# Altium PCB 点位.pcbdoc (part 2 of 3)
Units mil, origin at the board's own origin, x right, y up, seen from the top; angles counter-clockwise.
Board outline 2817.44 x 1578.14 mil, 2 copper layers (Top Layer, Bottom Layer); 132 components, 113 nets, 538 pads, 285 vias.

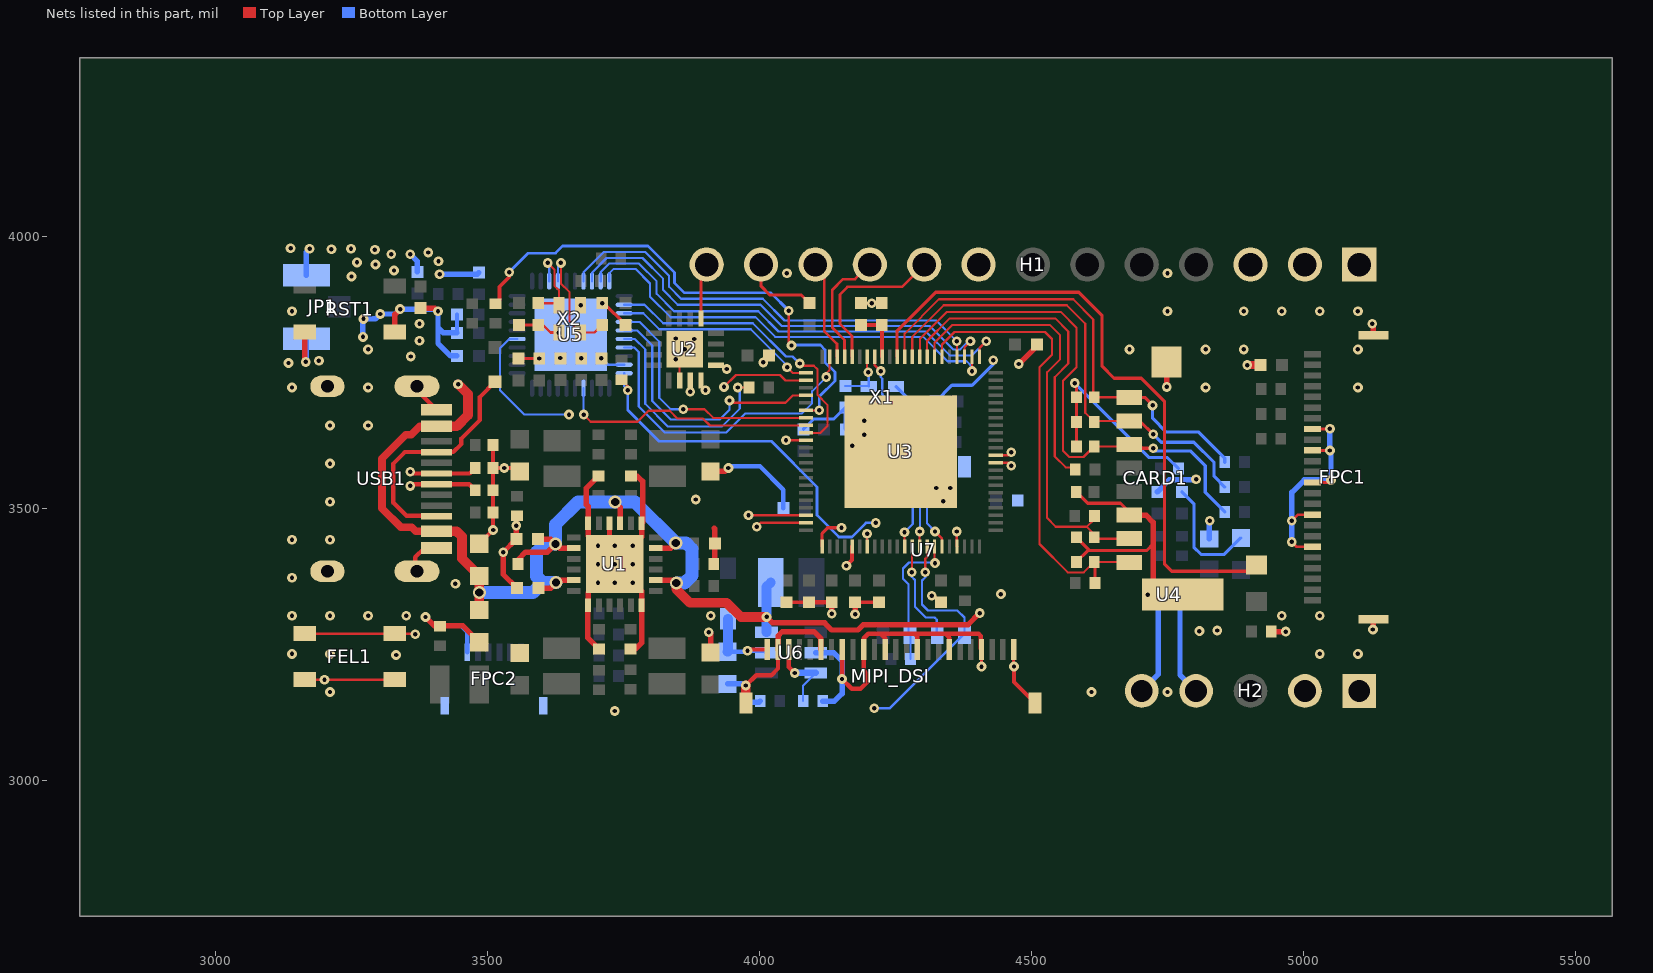
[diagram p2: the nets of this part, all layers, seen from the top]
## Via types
v1: diameter 18, hole 8, Top Layer to Bottom Layer, 271 vias
v2: diameter 24, hole 15, Top Layer to Bottom Layer, 14 vias

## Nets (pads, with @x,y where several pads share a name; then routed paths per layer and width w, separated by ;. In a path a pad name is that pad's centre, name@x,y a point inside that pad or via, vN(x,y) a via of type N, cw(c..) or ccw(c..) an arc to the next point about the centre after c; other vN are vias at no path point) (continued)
GND: C1.1 C2.1 C3.1 C4.1 C5.2 C6.1 C7.1 C8.1 C9.1 C10.2 C11.2 C13.1 C14.1 C15.2 C16.2 C17.1 C18.1 C19.1 C20.1 C21.2 C22.2 C23.2 C24.2 C25.2 C26.2 C27.2 C28.2 C29.2 C30.2 C31.2 C32.1 C33.2 C34.2 C35.1 C36.1 C37.1 C38.1 C39.2 C40.1 C41.1 C42.1 C43.1 C44.1 C45.1 C46.1 C47.1 CARD1.6 CARD1.9 CARD1.10 D1.2 D2.2 D3.2 D4.2 D6.1 D8.2 D9.2 D10.2 D11.2 D12.2 D13.2 FEL1.3 FEL1.4 FPC1.8 FPC1.10 FPC1.13 FPC1.16 FPC1.19 FPC1.25 FPC1.26 FPC2.6 FPC2.7 FPC2.8 H1.1 H1.12 H2.1 JP1.2 JP1.3 MIPI_DSI.1 MIPI_DSI.4 MIPI_DSI.7 MIPI_DSI.10 MIPI_DSI.13 MIPI_DSI.15 MIPI_DSI.17 MIPI_DSI.19 MIPI_DSI.23 MIPI_DSI.25 MIPI_DSI.26 R2.2 R5.2 R9.1 R11.2 R13.2 R23.1 R24.1 R25.2 R26.2 R27.1 RST1.1 RST1.2 U1.1 U1.4 U1.6 U1.13 U1.18 U1.25 U2.2 U2.17 U3.51 U3.89 U4.A2 U4.B3 U5.19 U5.41 U6.2 U7.4 USB1.12 USB1.13 USB1.14 USB1.15 USB1.A1B12 USB1.B1A12 X1.2 X1.4 X2.2 X2.4 | length 7017.8
  Top Layer w4: v1(3845.5,3812.13) 3852.72,3804.92 U2.2@3852.72,3735.05 ; U3.51@4197.49,3429.62 v1(4197.49,3453.12) ; v1(4316.5,3339.13) 4321.51,3339.13 C45.1@4333.5,3327.14
  Top Layer w5: FEL1.3@3165.8,3184.83 v1(3199.94,3184.83) FEL1.4@3331.2,3184.83 ; C21.2@3556.67,3775.24 v1(3594.67,3775.24) ; C23.2@3557.85,3836.98 3592.84,3836.98 3601.64,3836.99 3615.65,3822.99 v1(3630.85,3822.99) ; C17.1@4186.3,3877.05 v1(4206.02,3877.05) 4224.15,3877.05 C18.1@4224.43,3877.33 ; MIPI_DSI.4@4407.8,3240.33 v1(4407.8,3208.83) v1@4408.5,3208.13 ; MIPI_DSI.1@4466.9,3240.33 4466.9,3209.73 v1(4467.5,3209.13) ; v1(4978.5,3438.13) 4987.4,3429.23 FPC1.19@5016.69,3429.18 ; v1(4978.5,3477.13) 4989.6,3488.23 FPC1.16@5016.69,3488.24 ; FPC1.13@5016.69,3547.29 5045.7,3547.33 v1(5050.5,3552.13) ; FPC1.10@5016.7,3606.33 5048.3,3606.33 v1(5048.5,3606.13) ; FPC1.8@5017.1,3646.13 FPC1.8@5016.69,3645.72 5048.1,3645.73 v1(5048.5,3646.13)
  Top Layer w6: v1(3552.5,3468.13) 3553.5,3469.13 R27.1@3553.5,3486.13 ; v1(3710.5,3877.14) 3713.5,3877.14 C41.1@3753.5,3837.14 ; H1.12@4002.5,3948.13 4002.5,3908.13 4018.5,3892.13 4076.49,3892.13 C40.1@4091.5,3877.13 ; C38.1@4049.5,3327.14 C37.1@4090.5,3327.14 ; C11.2@4175.5,3327.13 C44.1@4219.5,3327.14 ; v1(4579.5,3730.13) 4582.44,3727.19 D13.2@4582.44,3704.21 D12.2@4582.44,3658.84 D11.2@4582.44,3613.47 ; D10.2@4582.1,3530.13 4603.1,3509.13 4663.42,3509.13 CARD1.6@4685.32,3487.23 ; D8.2@4582.44,3401.36 4603.22,3422.13 4607.04,3422.13 ; D9.2@4582.44,3446.73 4607.04,3422.13 ; 4723.5,3434.41 4711.22,3422.13 4607.04,3422.13
  Top Layer w7: C3.1@3484.5,3434.66 v1(3509.9,3460.06) D2.2@3509.9,3492.13 D3.2@3509.9,3533.13 D4.2@3509.9,3574.13 ; D1.2@3509.9,3616.13 D4.2@3509.9,3574.13 ; C4.1@3558.67,3567.75 3552.29,3574.13 v1(3530.37,3574.13) D4.2@3509.9,3574.13 ; v1(4467.5,3209.13) 4467.5,3180.73 MIPI_DSI.26@4506.3,3141.93
  Top Layer w8: USB1.13@3369.8,3384.03 3366.5,3387.33 3366.5,3410.13 3383.5,3427.13 USB1.B1A12@3405.8,3427.13 ; USB1.12@3369.8,3724.23 3369.8,3717.13 USB1.A1B12@3405.8,3681.13 ; v1(3974.5,3174.13) 3993.5,3193.13 4021.5,3193.13 4033.8,3205.43 MIPI_DSI.23@4033.8,3240.33 ; MIPI_DSI.17@4151.9,3240.33 4151.9,3186.53 v1(4151.5,3186.13) 4169.5,3168.13 4185.5,3168.13 4197.5,3180.13 4197.5,3195.13 4191.3,3201.33 MIPI_DSI.15@4191.3,3240.33 4191.3,3260.93 4199.5,3269.13 4222.5,3269.13 ; MIPI_DSI.13@4230.7,3240.33 4230.7,3260.93 4222.5,3269.13 ; MIPI_DSI.10@4289.7,3240.33 4289.5,3240.53 4289.5,3264.13 4284.5,3269.13 ; MIPI_DSI.7@4348.8,3240.33 4348.5,3240.63 4348.5,3262.13 4341.5,3269.13 ; MIPI_DSI.4@4407.8,3240.33 4406.5,3241.63 4406.5,3265.13 4402.5,3269.13 4341.5,3269.13 ; 4222.5,3269.13 4284.5,3269.13 ; 4284.5,3269.13 4341.5,3269.13
  Top Layer w9: C37.1@4090.5,3327.14 C10.2@4132.5,3327.13
  Top Layer w10: RST1.2@3163.8,3823.83 3163.8,3770.83 v1(3165.5,3769.13) ; RST1.1@3329.2,3823.83 3329.2,3856.45 v1(3338.88,3866.13) ; C5.2@3376.5,3868.13 3402.5,3868.13 v1(3408.5,3862.13) ; v1(3385.5,3300.13) 3401.5,3284.13 3453.97,3284.13 C2.1@3484.5,3253.61 ; v1(3552.5,3468.13) 3552.67,3467.97 C33.2@3552.67,3443.26 v1(3528.5,3419.09) 3528.5,3378.42 C34.2@3553.67,3353.26 ; v1(3702.67,3363.26) 3684.46,3345.05 U1.13@3684.46,3321.99 3683.67,3321.2 3683.67,3262.26 R2.2@3704.67,3241.25 ; v1(3702.67,3431.26) 3684.46,3449.47 U1.6@3684.46,3472.51 3684.46,3503.47 3681.32,3506.61 3681.32,3536.91 R5.2@3703.67,3559.26 ; U1.4@3723.83,3472.51 3723.83,3441.09 v1(3733.67,3431.26) ; R13.2@3762.67,3241.25 3771.67,3241.25 3782.88,3252.47 U1.18@3782.88,3321.99 3782.88,3347.05 v1(3766.67,3363.26) ; R11.2@3763.67,3559.26 3774.67,3559.26 3784.67,3549.26 3784.67,3474.3 U1.1@3782.88,3472.51 3782.88,3447.47 v1(3766.67,3431.26) ; v1(3906.5,3272.13) 3909.67,3268.96 C8.1@3909.67,3234.78 ; R9.1@3915.67,3397.25 3917.67,3399.25 C7.1@3917.67,3435.26 3917.67,3461.97 3916.5,3463.13 ; C6.1@3916.05,3574.13 C6.1@3909.67,3567.75 3936.12,3567.75 v1(3942.5,3574.13) ; MIPI_DSI.23@4033.8,3240.33 4033.8,3265.43 4041.5,3273.13 4099.5,3273.13 4112.5,3260.13 4112.5,3240.43 MIPI_DSI.19@4112.6,3240.33 ; v1(4132.5,3306.13) C10.2@4132.5,3327.13 ; v1(4175.5,3305.13) C11.2@4175.5,3327.13 ; v1(4476.5,3765.13) 4509.51,3798.14 C39.2@4509.51,3801.13 ; CARD1.6@4679.3,3487.23 4685.32,3487.23 4710.4,3487.23 4723.5,3474.13 4723.5,3434.41 4723.5,3350.52 v1(4713.85,3340.88) ; CARD1.10@4748.2,3768.73 4748.2,3723.43 v1(4748.5,3723.13) ; R25.2@4940.5,3273.14 v1(4967.5,3273.14) ; v1(5126.5,3839.13) 5128.3,3837.33 FPC1.26@5128.3,3818.33 ; v1(5127.5,3277.13) 5128.3,3277.93 FPC1.25@5128.31,3295.91
  Top Layer w15: v1(4896.5,3763.13) C35.1@4920.51,3763.13
  Top Layer w18: v1(3974.5,3174.13) 3974.5,3142.23 MIPI_DSI.25@3974.8,3141.93
  Mid-Layer 2 w10: v1(3879.5,3811.13) 3897.5,3811.13 3925.5,3839.13 3977.5,3839.13 4006.5,3810.13 v1(4006.5,3768.13)
  Bottom Layer w4: v1(4192.5,3635.13) v1(4192.5,3661.13) 4200.5,3669.13 X1.4@4200.5,3684.05 ; C15.2@4203.57,3635.13 C15.2@4214.49,3646.05
  Bottom Layer w5: v1(3708.95,3775.71) 3720.65,3764.01 U5.19@3750.9,3764.01 ; v1(4192.5,3635.13) 4203.57,3635.13 4220.5,3635.13 4235.5,3620.13 4263.5,3620.13 4281.5,3638.13 4281.5,3693.05 4278.42,3696.13
  Bottom Layer w6: C43.1@4080.5,3645.13 4099.51,3664.13 4136.58,3664.13 C16.2@4157.5,3685.05 4157.5,3646.13 C42.1@4158.49,3645.13 ; X1.2@4250.5,3724.05 4278.42,3696.13 C36.1@4323.51,3696.13 4353.51,3726.13 4390.5,3726.13 4429.5,3765.13 v1(4429.5,3772.13) ; v1(4579.5,3730.13) 4716.5,3593.13 4749.9,3593.13 D6.1@4769.9,3573.13 ; U4.A2@4732.85,3340.88 U4.B3@4752.85,3320.88 ; C13.1@4776.36,3530.3 4798.5,3508.16 4798.5,3428.13 4811.5,3415.13 4854.58,3415.13 C14.1@4884.85,3445.4
  Bottom Layer w8: v1(3385.5,3300.13) 3400.5,3285.13 3449.5,3285.13 3462.3,3272.33 FPC2.6@3462.3,3235.33 ; C22.2@3443.46,3822.36 C24.2@3443.46,3856.36 ; v1(3942.5,3574.13) 3942.5,3576.13 3943.5,3577.13 4000.5,3577.13 4043.51,3534.13 C46.1@4043.51,3500.13 ; v1(4713.85,3340.88) U4.A2@4732.85,3340.88
  Bottom Layer w10: v1(3165.5,3769.13) 3166.49,3770.12 JP1.3@3166.49,3812.06 ; JP1.2@3166.49,3928.2 3166.49,3971.12 v1(3172.5,3977.13) ; v1(3270.5,3815.13) 3270.5,3847.13 v1(3271.5,3848.13) 3293.5,3848.13 v1(3302.5,3857.13) 3329.88,3857.13 v1(3338.88,3866.13) 3404.5,3866.13 v1(3408.5,3862.13) 3408.5,3832.13 3409.5,3831.13 ; v1(3357.5,3967.13) 3370.64,3953.99 C20.1@3370.64,3934.48 ; v1(3411.5,3930.13) 3480.29,3930.13 C19.1@3483.64,3933.48 ; C22.2@3443.46,3822.36 3418.27,3822.36 3409.5,3831.13 ; C27.2@3443.49,3780.13 3431.5,3780.13 3408.5,3803.13 3408.5,3830.13 3409.5,3831.13 ; C32.1@3940.92,3177.01 3971.62,3177.01 v1(3974.5,3174.13) 3974.5,3153.13 3984.5,3143.13 3998.52,3143.13 R23.1@4000.92,3145.53 ; U6.2@4103.12,3234.54 4136.1,3234.54 4151.5,3219.13 v1(4151.5,3186.13) 4151.5,3159.13 4137.5,3145.13 4116.32,3145.13 R24.1@4115.92,3145.54 ; v1(4978.5,3438.13) v1(4978.5,3477.13) 4978.5,3529.13 5001.5,3552.13 v1(5050.5,3552.13) 5050.5,3604.13 v1(5048.5,3606.13) v1(5048.5,3646.13)
  other v1: 3733.5,3127.13 3210,3162.14 4610,3162.14 4750,3162.14 3331.5,3230.13 3140,3232.14 3210,3232.14 5030,3232.14 5100,3232.14 3140,3302.14 3210,3302.14 3280,3302.14 3350,3302.14 3910,3302.14 4960,3302.14 5030,3302.14 4443.5,3342.13 3440.5,3361.13 3733.67,3363.26 3140,3372.14 3702.67,3397.26 3733.67,3397.26 3766.67,3397.26 3140,3442.14 3210,3442.14 3210,3512.14 4337.5,3513.13 3882.5,3516.13 4324.5,3537.13 4350.5,3537.13 3210,3582.14 4170.5,3615.13 3210,3652.14 3280,3652.14 3140,3722.14 3280,3722.14 4820,3722.14 5100,3722.14 3133.5,3767.13 3189.5,3771.13 3845.5,3774.13 3633.5,3776.13 3671.95,3775.71 3358.5,3779.13 3280,3792.14 3862.51,3792.13 4680,3792.14 4820,3792.14 4890,3792.14 5100,3792.14 3374.5,3807.83 3374.5,3839.13 3140,3862.14 4750,3862.14 4890,3862.14 4960,3862.14 5030,3862.14 5100,3862.14 3670.85,3872.99 3249.5,3926.13 4050,3932.14 4750,3932.14 3327.5,3937.13 3293.5,3948.13 3259.5,3952.13 3409.5,3954.13 3322.5,3967.13 3390.5,3970.13 3292.5,3975.13 3212.5,3976.13 3248.5,3977.13 3137.5,3978.13
HX1: C30.1 U5.3 X2.1 | length 160.9
  Top Layer w4: C30.1@3592.85,3876.99 3626.85,3876.99 X2.1@3630.85,3872.99 3630.85,3900.78 3622.5,3909.13 3622.5,3939.13 v1(3610.5,3951.13)
  Bottom Layer w4: v1(3610.5,3951.13) 3613.13,3948.5 U5.3@3613.13,3917.53
HX2: C31.1 U5.4 X2.3 | length 224.6
  Top Layer w4: v1(3634.5,3951.13) 3634.5,3913.13 3650.5,3897.13 3650.5,3843.34 X2.3@3670.85,3822.99 3696.35,3822.99 C31.1@3710.5,3837.14
  Bottom Layer w4: U5.4@3628.88,3917.53 3628.88,3945.51 v1(3634.5,3951.13)
HXIN: C16.1 U3.16 X1.1 | length 99.2
  Top Layer w4: U3.16@4197.49,3778.64 4197.49,3752.14 v1(4199.5,3750.13)
  Bottom Layer w4: C16.1@4157.5,3725.05 4199.5,3725.05 X1.1@4200.5,3724.05 4200.5,3749.14 v1(4199.5,3750.13)
HXOUT: C15.1 U3.15 X1.3 | length 150.5
  Top Layer w4: U3.15@4211.27,3778.64 4211.27,3763.36 v1(4222.5,3752.13)
  Bottom Layer w4: v1(4222.5,3752.13) 4222.5,3741.13 4225.5,3738.13 4225.5,3709.05 X1.3@4250.5,3684.05 4254.49,3680.06 C15.1@4254.49,3646.05
LED: LED1.2 U3.12 | length 1184.7
  Top Layer w6: U3.12@4252.61,3778.64 4252.61,3826.24 4323.5,3897.13 4586.5,3897.13 4629.5,3854.13 4629.5,3761.13 4651.5,3739.13 4701.5,3739.13 4744.5,3696.13 4744.5,3397.13 4757.5,3384.13 4902.04,3384.13 LED1.2@4913.5,3395.6
LEDA: C32.2 D7.1 MIPI_DSI.24 U6.5 | length 172.8
  Top Layer w8: v1(3977.5,3238.13) 3979.7,3240.33 MIPI_DSI.24@4014.1,3240.33
  Bottom Layer w8: C32.2@3940.92,3236.06 3975.43,3236.06 v1(3977.5,3238.13) 4009.12,3238.13 U6.5@4012.72,3234.54
  Bottom Layer w18: C32.2@3940.92,3236.06 3941.5,3236.64 D7.1@3941.5,3296.93
LEDK: MIPI_DSI.22 R24.2 U6.3 | length 147.6
  Top Layer w8: MIPI_DSI.22@4053.5,3240.33 4053.5,3208.13 v1(4064.5,3197.13)
  Bottom Layer w4: R24.2@4079.92,3145.54 4079.92,3173.94 U6.3@4103.12,3197.14
  Bottom Layer w12: v1(4064.5,3197.13) U6.3@4103.12,3197.14
LINEOUTP: C12.1 U3.49 | length 1142.3
  Top Layer w7: v1(4159.5,3394.13) 4169.93,3404.56 U3.49@4169.93,3429.62
  Mid-Layer 1 w7: v1(4159.5,3394.13) 4302.5,3251.13 4456.5,3251.13 4491.5,3286.13 4796.5,3286.13 v1(4808.5,3274.13)
  Mid-Layer 2 w7: v1(4802.5,3553.13) 4807.5,3548.13 4807.5,3467.13 4823.5,3451.13 4823.5,3289.13 v1(4808.5,3274.13)
  Bottom Layer w10: C12.1@4731.05,3530.3 4752.88,3552.13 4798.5,3552.13 4799.5,3553.13 v1(4802.5,3553.13)
LPCLK: R18.1 U3.63 U5.20 | length 871.8
  Top Layer w4: R18.1@3745.67,3736.24 3757.5,3724.41 v1(3757.5,3717.13)
  Top Layer w5: v1(4362.5,3457.13) 4362.5,3429.97 U3.63@4362.85,3429.62
  Mid-Layer 1 w5: v1(4213.5,3473.13) 4346.5,3473.13 v1(4362.5,3457.13)
  Bottom Layer w4: U5.20@3750.9,3748.26 3750.9,3723.73 v1(3757.5,3717.13)
  Bottom Layer w5: v1(3757.5,3717.13) 3757.5,3680.13 3814.5,3623.13 4021.5,3623.13 4105.5,3539.13 4105.5,3487.21 4145.58,3447.13 4169.5,3447.13 4195.5,3473.13 v1(4213.5,3473.13)
PE10: H1.8 U3.32 | length 573
  Top Layer w5: v1(4048.5,3625.13) 4048.83,3624.8 U3.32@4084.99,3624.8
  Mid-Layer 2 w4: v1(4048.5,3625.13) 4087.5,3664.13 4087.5,3747.13 4144.5,3804.13 4187.5,3804.13 4289.5,3906.13 4360.5,3906.13 H1.8@4402.5,3948.13
PE11: H1.11 U3.20 | length 186
  Top Layer w5: H1.11@4102.5,3948.13 4118.5,3932.13 4118.5,3826.13 4142.37,3802.26 U3.20@4142.37,3778.64
PE12: H1.10 U3.19 | length 220.3
  Top Layer w5: U3.19@4156.15,3778.64 4156.15,3809.48 4133.5,3832.13 4133.5,3901.13 4153.5,3921.13 4175.5,3921.13 H1.10@4202.5,3948.13
PE13: H1.9 U3.18 | length 301.6
  Top Layer w5: U3.18@4169.93,3778.64 4169.93,3816.7 4147.5,3839.13 4147.5,3893.13 4161.5,3907.13 4261.5,3907.13 H1.9@4302.5,3948.13
PH0: H2.2 U3.45 | length 1113.8
  Top Layer w6: U3.45@4114.81,3429.62 4114.81,3453.68 4125.26,3464.13 v1(4150.5,3464.13)
  Mid-Layer 1 w6: v1(4150.5,3464.13) 4132.5,3446.13 4132.5,3398.13 4295.5,3235.13 4947.5,3235.13 5002.5,3180.13 H2.2@5002.5,3164.13
SDC0_CLK: R42.1 U3.8 | length 604
  Top Layer w4: U3.8@4307.73,3778.64 4307.73,3807.36 4349.5,3849.13 4543.5,3849.13 4567.5,3825.13 4567.5,3766.13 4542.5,3741.13 4542.5,3595.13 4562.5,3575.13 4576.51,3575.13 R42.1@4580.5,3571.14
SDC0_CMD: CARD1.3 D11.1 R31.1 U3.9 | length 982.1
  Top Layer w4: U3.9@4293.95,3778.64 4294.5,3779.19 4294.5,3811.13 4344.5,3861.13 4553.5,3861.13 4582.5,3832.13 4582.5,3759.13 4557.5,3734.13 4557.5,3606.13 4569.5,3594.13 4595.5,3594.13 4614.83,3613.47 D11.1@4615.24,3613.47 4675.63,3613.47 CARD1.3@4679.3,3617.13
  Top Layer w6: CARD1.3@4679.3,3617.13 4696.5,3617.13 4703.5,3610.13 v1(4723.5,3610.13)
  Bottom Layer w6: v1(4723.5,3610.13) 4728.5,3605.13 4792.5,3605.13 4819.5,3578.13 4819.5,3529.15 R31.1@4855.34,3493.31
SDC0_D0: CARD1.7 D9.1 R29.1 U3.7 | length 819.7
  Top Layer w4: U3.7@4321.51,3778.64 4321.51,3804.14 4354.5,3837.13 4533.5,3837.13 4552.5,3818.13 4552.5,3774.13 4528.5,3750.13 4528.5,3482.13 4544.5,3466.13 4601.5,3466.13 ; R29.1@4615.5,3486.13 4615.5,3480.13 4601.5,3466.13 ; CARD1.7@4679.3,3443.93 4618.04,3443.93 D9.1@4615.24,3446.73 4615.24,3452.39 4601.5,3466.13
SDC0_D1: CARD1.8 D8.1 R28.1 U3.6 | length 863.2
  Top Layer w4: U3.6@4335.29,3778.64 4335.29,3801.14 4358.29,3824.13 4524.5,3824.13 4537.5,3811.13 4537.5,3782.13 4514.5,3759.13 4514.5,3434.13 4566.5,3382.13 4596.02,3382.13 4613.78,3399.9 D8.1@4615.24,3401.36 ; D8.1@4611.72,3401.36 D8.1@4615.24,3401.36 ; CARD1.8@4679.3,3400.63 4678.58,3401.36 D8.1@4615.24,3401.36
  Top Layer w6: D8.1@4613.78,3399.9 4616.5,3397.18 R28.1@4616.5,3362.13
SDC0_D2: CARD1.1 D13.1 R33.1 U3.11 | length 882.7
  Top Layer w4: U3.11@4266.39,3778.64 4266.5,3778.75 4266.5,3821.13 4329.5,3884.13 4576.5,3884.13 4613.5,3847.13 4613.5,3705.95 D13.1@4615.24,3704.21 4678.83,3704.21 CARD1.1@4679.3,3703.73
  Top Layer w6: CARD1.1@4679.3,3703.73 4707.9,3703.73 v1(4722.5,3689.13)
  Bottom Layer w6: v1(4722.5,3689.13) 4722.5,3665.13 4747.5,3640.13 4807.5,3640.13 4855.34,3592.29 R33.1@4855.34,3584.68
SDC0_D3: CARD1.2 D12.1 R32.1 U3.10 | length 885.8
  Top Layer w4: U3.10@4280.17,3778.64 4280.5,3778.97 4280.5,3815.13 4338.5,3873.13 4564.5,3873.13 4598.5,3839.13 4598.5,3675.58 D12.1@4615.24,3658.84 4616.84,3660.43 CARD1.2@4679.3,3660.43
  Top Layer w6: CARD1.2@4679.3,3660.43 4699.2,3660.43 v1(4723.5,3636.13)
  Bottom Layer w6: v1(4723.5,3636.13) 4738.5,3621.13 4798.5,3621.13 4835.5,3584.13 4835.5,3558.83 R32.1@4855.34,3538.99
SDC1_CLK: R22.1 U5.16 | length 413.2
  Top Layer w4: v1(3959.5,3722.13) R22.1@3980.5,3722.14
  Bottom Layer w4: U5.16@3750.9,3811.26 3770.37,3811.26 3789.5,3792.13 3789.5,3692.13 3831.5,3650.13 3930.5,3650.13 3963.5,3683.13 3963.5,3718.13 v1(3959.5,3722.13)
SDC1_CMD: U3.31 U5.12 | length 561.1
  Top Layer w4: v1(4073.5,3766.13) 4077.5,3762.13 4099.5,3762.13 4106.5,3755.13 4106.5,3708.13 4124.5,3690.13 4124.5,3651.13 4111.95,3638.58 U3.31@4084.99,3638.58
  Bottom Layer w4: U5.12@3750.9,3874.25 3788.38,3874.25 3822.5,3840.13 3987.5,3840.13 4048.5,3779.13 4060.5,3779.13 v1(4073.5,3766.13)
SDC1_D0: U3.23 U5.13 | length 381.3
  Top Layer w4: v1(4050.5,3759.13) 4060.81,3748.82 U3.23@4084.99,3748.82
  Bottom Layer w4: U5.13@3750.9,3858.5 3786.13,3858.5 3815.5,3829.13 3983.5,3829.13 4050.5,3762.13 v1(4050.5,3759.13)
SDC1_D1: U3.29 U5.14 | length 467.6
  Top Layer w4: v1(3859.5,3682.13) 3898.5,3682.13 3914.49,3666.14 U3.29@4084.99,3666.14
  Bottom Layer w4: U5.14@3750.9,3842.75 3778.88,3842.75 3815.5,3806.13 3815.5,3703.13 3836.5,3682.13 v1(3859.5,3682.13)
SDC1_D2: U3.21 U5.17 | length 590.1
  Top Layer w4: v1(4122.5,3741.13) 4122.5,3748.13 4128.59,3754.22 U3.21@4128.59,3778.64
  Bottom Layer w4: U5.17@3750.9,3795.51 3769.12,3795.51 3777.5,3787.13 3777.5,3687.13 3825.5,3639.13 3938.5,3639.13 3973.5,3674.13 4077.5,3674.13 4096.5,3693.13 4096.5,3715.13 v1(4122.5,3741.13)
SDC1_D3: U3.26 U5.15 | length 493.4
  Top Layer w4: v1(3944.5,3698.13) 3948.5,3694.13 4047.5,3694.13 4060.85,3707.48 U3.26@4084.99,3707.48
  Bottom Layer w4: U5.15@3750.9,3827 3774.63,3827 3802.5,3799.13 3802.5,3697.13 3836.5,3663.13 3926.5,3663.13 3944.5,3681.13 v1(3944.5,3698.13)
SPI0_CLK: U3.57 U7.6 | length 189.1
  Top Layer w4: v1(4279.5,3382.13) 4280.17,3382.8 U3.57@4280.17,3429.62
  Bottom Layer w4: v1(4279.5,3382.13) 4279.5,3374.13 4285.5,3368.13 4285.5,3319.13 4305.5,3299.13 4321.5,3299.13 4325.5,3295.13 4325.5,3270.63 U7.6@4326.5,3269.63
SPI0_CS: R34.1 U3.56 U7.1 | length 339.8
  Top Layer w4: U3.56@4266.39,3429.62 4266.5,3456.13 v1(4266.39,3456.02)
  Bottom Layer w4: U7.1@4226.5,3576.63 4226.5,3556.13 4236.5,3546.13 4256.5,3546.13 4262.5,3540.13 4262.5,3526.13 4281.5,3507.13 4281.5,3471.13 v1(4266.39,3456.02)
  Bottom Layer w5: U7.1@4226.5,3576.63 4226.5,3589.13 4244.5,3607.13 4294.5,3607.13 4307.5,3620.13 4307.5,3640.12 R34.1@4325.5,3658.13
SPI0_HOLD: R36.1 U3.60 U7.7 | length 266.7
  Top Layer w4: U3.60@4321.51,3429.62 4321.51,3400.12 v1(4322.5,3399.13)
  Bottom Layer w4: R36.1@4277.5,3223.14 4277.5,3268.63 U7.7@4276.5,3269.63 4273.5,3272.63 4273.5,3360.13 4263.5,3370.13 4263.5,3389.13 4274.5,3400.13 4321.5,3400.13 v1(4322.5,3399.13)
SPI0_MISO: U3.58 U7.2 | length 154.7
  Top Layer w4: U3.58@4293.95,3429.62 4293.95,3456.58 v1(4294.5,3457.13)
  Bottom Layer w4: U7.2@4276.5,3576.63 4276.5,3531.13 4294.5,3513.13 v1(4294.5,3457.13)
SPI0_MOSI: FEL1.1 FEL1.2 U3.59 U7.5 | length 1587.1
  Top Layer w4: v1(4304.5,3382.13) 4304.5,3407.13 4307.73,3410.36 U3.59@4307.73,3429.62
  Top Layer w5: FEL1.1@3165.8,3269.43 3331.2,3269.43 3365.2,3269.43 v1(3366.5,3268.13)
  Mid-Layer 1 w6: v1(3366.5,3268.13) 3382.5,3284.13 3410.5,3284.13 3436.5,3310.13 3623.5,3310.13 3756.5,3177.13 3799.5,3177.13 3844.5,3132.13 v1(4210.5,3132.13)
  Bottom Layer w4: v1(4304.5,3382.13) 4304.5,3373.13 4298.5,3367.13 4298.5,3323.13 4309.5,3312.13 4363.5,3312.13 4376.5,3299.13 U7.5@4376.5,3269.63
  Bottom Layer w5: v1(4210.5,3132.13) 4239,3132.13 U7.5@4376.5,3269.63
SPI0_WP: R35.1 U3.61 U7.3 | length 224.8
  Top Layer w4: v1(4322.5,3457.13) 4335.28,3444.35 U3.61@4335.28,3429.62
  Bottom Layer w4: v1(4322.5,3457.13) 4307.5,3472.13 4307.5,3519.13 4293.5,3533.13 4293.5,3545.13 4325,3576.63 U7.3@4326.5,3576.63 4325.5,3577.63 R35.1@4325.5,3622.13
SPK+: H2.4 U4.C3 | length 169
  Bottom Layer w10: U4.C3@4772.85,3320.88 4772.85,3193.78 H2.4@4802.5,3164.13
SPK-: H2.5 U4.A3 | length 169.3
  Bottom Layer w10: H2.5@4702.5,3164.13 4732.85,3194.49 U4.A3@4732.85,3320.88
UART0_RX: H1.3 U2.4 U3.42 | length 1842.1
  Top Layer w4: U2.4@3892.09,3735.04 3892.09,3725.55 v1(3900.5,3717.13) ; v1(3979.5,3487.13) 3979.63,3487 U3.42@4084.99,3487
  Mid-Layer 1 w5: v1(3900.5,3717.13) 3923.5,3740.13 3954.5,3740.13 3955.5,3741.13 4023.5,3741.13 4081.28,3683.35 4081.28,3512.91 4055.5,3487.13 v1(3979.5,3487.13)
  Mid-Layer 2 w4: v1(3979.5,3487.13) 3987.5,3495.13 4161.5,3495.13 4294.5,3628.13 4294.5,3805.13 4329.5,3840.13 4794.5,3840.13 H1.3@4902.5,3948.13
UART0_TX: H1.2 U2.5 U3.43 | length 1905.5
  Top Layer w4: U2.5@3919.59,3762.61 3933.02,3762.61 v1(3939.5,3756.13) ; v1(3994.5,3466.13) 4001.59,3473.22 U3.43@4084.99,3473.22
  Mid-Layer 1 w5: v1(3939.5,3756.13) 3943.5,3752.13 4029.5,3752.13 4092.28,3689.35 4092.28,3506.91 4059.5,3474.13 4002.5,3474.13 v1(3994.5,3466.13)
  Mid-Layer 2 w4: v1(3994.5,3466.13) 4009.5,3481.13 4168.5,3481.13 4307.5,3620.13 4307.5,3798.13 4334.5,3825.13 4879.5,3825.13 H1.2@5002.5,3948.13
UART2_CTS: U3.4 U5.7 | length 826.4
  Top Layer w4: v1(4362.5,3807.13) 4362.85,3806.78 U3.4@4362.85,3778.64
  Bottom Layer w4: U5.7@3676.12,3917.53 3676.12,3933.75 3713.5,3971.13 3789.5,3971.13 3833.5,3927.13 3833.5,3907.13 3855.5,3885.13 4005.5,3885.13 4045.5,3845.13 4324.5,3845.13 v1(4362.5,3807.13)
UART2_RTS: U3.3 U5.8 | length 843.7
  Top Layer w4: U3.3@4376.63,3778.64 4376.63,3796.26 v1(4387.5,3807.13)
  Bottom Layer w4: U5.8@3691.87,3917.53 3691.87,3933.5 3718.5,3960.13 3784.5,3960.13 3822.5,3922.13 3822.5,3901.13 3849.5,3874.13 4001.5,3874.13 4040.5,3835.13 4312.5,3835.13 4355.5,3792.13 4368.71,3792.13 4383.71,3807.13 v1(4387.5,3807.13)
UART2_RX: U3.2 U5.10 | length 808.1
  Top Layer w4: U3.2@4390.41,3778.64 4390.41,3752.22 v1(4390.5,3752.13)
  Bottom Layer w4: U5.10@3723.37,3917.53 3723.37,3932 3731.5,3940.13 3771.5,3940.13 3798.5,3913.13 3798.5,3889.13 3836.5,3851.13 3992.5,3851.13 4028.5,3815.13 4300.5,3815.13 4345.5,3770.13 4380.5,3770.13 4390.5,3760.13 v1(4390.5,3752.13)
UART2_TX: U3.1 U5.9 | length 860.2
  Top Layer w4: U3.1@4404.19,3778.64 4404.19,3794.82 v1(4416.5,3807.13)
  Bottom Layer w4: U5.9@3707.62,3917.53 3707.62,3934.25 3723.5,3950.13 3777.83,3950.13 3810.5,3917.46 3810.5,3894.13 3842.5,3862.13 3997.5,3862.13 4034.5,3825.13 4305.5,3825.13 4349.5,3781.13 4390.5,3781.13 v1(4416.5,3807.13)
USB0_ID: D5.2 USB1.A5 USB1.B5 | length 441.7
  Top Layer w8: USB1.B5@3405.8,3485.23 3404.9,3486.13 3350.5,3486.13 3326.5,3510.13 3326.5,3582.13 3347.7,3603.33 USB1.A5@3405.8,3603.33 3436.7,3603.33 3451.5,3618.13 3451.5,3628.13 3485.5,3662.13 3485.5,3704.63 D5.2@3513.5,3732.63
USB_D+: D4.1 U3.76 USB1.A6 | length 1674
  Top Layer w5: U3.76@4434.01,3583.46 4457.17,3583.46 v1(4462.5,3578.13)
  Top Layer w8: v1(3357.5,3567.13) 3360.7,3563.93 USB1.A6@3405.8,3563.93 3466.9,3563.93 D4.1@3477.1,3574.13
  Mid-Layer 1 w5: v1(3357.5,3567.13) 3341,3567.13 3333.5,3559.63 3325.61,3559.63 3309.97,3575.27 3309.97,3593.52 3326.59,3610.13 3447.17,3610.13 3534.5,3697.47 3534.5,3760.13 3569.34,3794.97 3794.34,3794.97 3833.5,3834.13 4195.5,3834.13 4363.23,3666.4 4363.23,3597.9 4385.28,3575.86 4416.38,3575.86 4425.66,3585.13 4439,3585.13 4446,3578.13 v1(4462.5,3578.13)
USB_D-: D3.1 U3.77 USB1.A7 | length 1713.6
  Top Layer w5: U3.77@4434.01,3597.24 4456.61,3597.24 v1(4462.5,3603.13)
  Top Layer w8: v1(3357.5,3541.13) 3360.7,3544.33 USB1.A7@3405.8,3544.33 3465.9,3544.33 D3.1@3477.1,3533.13
  Mid-Layer 1 w5: v1(3357.5,3541.13) 3341,3541.13 3333.5,3548.63 3318.11,3548.63 3298.97,3567.77 3298.97,3598.07 3322.03,3621.13 3442.61,3621.13 3523.5,3702.02 3523.5,3766.13 3563.34,3805.97 3790.34,3805.97 3829.5,3845.13 4200.06,3845.13 4374.23,3670.96 4374.23,3602.46 4389.83,3586.86 4411.83,3586.86 4421.1,3596.13 4439,3596.13 4446,3603.13 v1(4462.5,3603.13)
USB_ID: R10.1 U3.28 | length 950.4
  Top Layer w4: U3.28@4084.99,3679.92 4109.29,3679.92 v1(4109.5,3680.13)
  Top Layer w5: v1(4053.5,3863.13) 4053.5,3804.13 v1(4058.5,3799.13)
  Top Layer w7: R10.1@3513.83,3875.92 3521.5,3883.59 3521.5,3907.13 3539.5,3925.13 v1(3539.5,3934.13)
  Bottom Layer w5: v1(3539.5,3934.13) 3574.5,3969.13 3624.5,3969.13 3637.5,3982.13 3794.5,3982.13 3843.5,3933.13 3843.5,3914.13 3861.5,3896.13 4020.5,3896.13 v1(4053.5,3863.13) ; v1(4058.5,3799.13) 4059.5,3800.13 4111.5,3800.13 4120.5,3791.13 4120.5,3768.13 4138.5,3750.13 4138.5,3734.13 4109.5,3705.13 v1(4109.5,3680.13)
VBUS: C2.2 C3.2 C33.1 C34.1 H1.13 L5.1 L6.1 R3.2 U1.3 U1.8 U1.11 U1.20 U1.23 U2.3 U2.9 U6.6 USB1.A4B9 USB1.B4A9 | length 4231.5
  Top Layer w4: U2.3@3872.41,3735.05 3872.41,3714.23 v1(3872.5,3714.13)
  Top Layer w6: U2.9@3892.03,3849.22 3892.03,3937.66 H1.13@3902.5,3948.13
  Top Layer w10: R3.2@3555.67,3397.25 3555.67,3405.25 3569.67,3419.26 3609.67,3419.26 v2(3624.67,3434.26) ; C33.1@3592.67,3443.26 3615.67,3443.26 v2(3624.67,3434.26) ; C34.1@3593.67,3353.26 3615.67,3353.26 v2(3625.67,3363.26) 3630.14,3367.72 U1.11@3658.41,3367.72 ; U1.8@3658.41,3426.78 3632.14,3426.78 v2(3624.67,3434.26) ; v2(3734.32,3511.18) 3743.51,3501.99 U1.3@3743.51,3472.51 ; U1.20@3808.93,3367.72 3841.2,3367.72 v2(3846.67,3362.26) ; U1.23@3808.93,3426.78 3836.2,3426.78 v2(3845.67,3436.26) ; v1(4012.72,3300.2) 4023.79,3289.13 4119.5,3289.13 4132.5,3276.13 4180.5,3276.13 4190.5,3286.13 4383.5,3286.13 v1(4404.5,3307.13)
  Top Layer w14: USB1.B4A9@3405.8,3457.63 3368,3457.63 3360.5,3465.13 3340.5,3465.13 3305.5,3500.13 3305.5,3591.13 3349.5,3635.13 3359.5,3635.13 3375,3650.63 USB1.A4B9@3405.8,3650.63
  Top Layer w18: USB1.B4A9@3405.8,3457.63 3443,3457.63 3452.5,3448.13 3452.5,3407.6 C3.2@3484.5,3375.6 v2(3484.5,3344.85) C2.2@3484.5,3312.66 ; USB1.A4B9@3405.8,3650.63 3443,3650.63 3463.5,3671.13 3463.5,3710.13 v1(3445.5,3728.13) ; v2(3846.67,3362.26) 3846.67,3350.96 3871.5,3326.13 3939.5,3326.13 3965.43,3300.2 v1(4012.72,3300.2)
  Mid-Layer 1 w10: v2(3734.32,3511.18) 3733.5,3512 3733.5,3655.13 3805.5,3727.13 3859.5,3727.13 v1(3872.5,3714.13) ; v1(4404.5,3307.13) 4407.5,3304.13 4812.5,3304.13 v1(4841.5,3275.13)
  Mid-Layer 1 w18: v1(3445.5,3728.13) 3445.5,3926.13 3505.5,3986.13 3864.5,3986.13 H1.13@3902.5,3948.13
  Mid-Layer 2 w10: v1(4827.5,3477.13) 4841.5,3463.13 v1(4841.5,3275.13)
  Bottom Layer w10: L5.1@4826.85,3443.43 4826.85,3476.48 v1(4827.5,3477.13)
  Bottom Layer w18: U6.6@4012.72,3271.94 v1(4012.72,3300.2) 4012.72,3355.74 L6.1@4020.52,3363.54
  Bottom Layer w24: v2(3484.5,3344.85) 3582.98,3344.85 3601.38,3363.26 ; v2(3625.67,3363.26) 3601.38,3363.26 ; v2(3846.67,3362.26) 3861.62,3362.26 3875.5,3376.13 3875.5,3425.13 3864.38,3436.26 v2(3845.67,3436.26) 3770.75,3511.18 v2(3734.32,3511.18) 3665.55,3511.18 3624.5,3470.13 3624.5,3434.43 v2(3624.67,3434.26) 3624.55,3434.13 3604.5,3434.13 3589.67,3419.3 3589.67,3374.96 3601.38,3363.26
VCC_LDOA: C17.2 C18.2 U3.14 | length 97
  Top Layer w7: C17.2@4186.3,3837.05 C18.2@4224.15,3837.05 ; C18.2@4224.43,3837.33 C18.2@4224.15,3837.05 ; U3.14@4225.05,3778.64 4225.05,3836.15 C18.2@4224.15,3837.05
WL_REG_ON: U3.30 U5.24 | length 482.2
  Top Layer w4: v1(3676.5,3672.13) 3689.5,3659.13 3775.5,3659.13 3795.5,3679.13 3834.5,3679.13 3848.5,3665.13 3895.5,3665.13 3908.5,3652.13 4084.76,3652.13 U3.30@4084.99,3652.36
  Bottom Layer w4: U5.24@3676.12,3720.73 3676.12,3672.51 v1(3676.5,3672.13)
WL_WAKE_AP: U3.24 U5.35 | length 745.3
  Top Layer w4: v1(3934.5,3723.13) 3956.5,3745.13 4037.5,3745.13 4047.59,3735.04 U3.24@4084.99,3735.04
  Mid-Layer 2 w4: v1(3649.5,3672.13) 3666.5,3655.13 3751.5,3655.13 3786.5,3690.13 3842.5,3690.13 3851.5,3699.13 3910.5,3699.13 v1(3934.5,3723.13)
  Bottom Layer w4: U5.35@3554.1,3811.26 3539.63,3811.26 3522.5,3794.13 3522.5,3717.13 3567.5,3672.13 v1(3649.5,3672.13)
"": 
pads on no net: FPC1.1 FPC1.2 FPC1.20 FPC1.21 FPC1.22 FPC1.23 FPC1.24 MIPI_DSI.16 MIPI_DSI.20 MIPI_DSI.21 U1.15 U1.16 U2.10 U2.11 U2.12 U2.13 U2.14 U2.15 U2.16 U3.46 U3.52 U3.53 U3.65 U5.18 U5.27 U5.29 U5.31 U5.32 U5.33 U5.34 U5.39 USB1.A8 USB1.B8

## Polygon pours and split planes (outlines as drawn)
GND on Mid-Layer 1 (solid, remove dead copper, pour order 1): 3006.49,3016.56 5251.49,3016.56 5251.49,4072.56 3006.49,4072.56
3V3 on Mid-Layer 2 (solid, remove dead copper, pour order 2): 3015,3008.13 5260,3008.13 5260,4064.13 3015,4064.13
GND on Bottom Layer (solid, remove dead copper, pour order 3): 3023,3000 5268,3000 5268,4056 3023,4056
GND on Top Layer (solid, remove dead copper, pour order 4): 3000,3022.14 5245,3022.14 5245,4078.14 3000,4078.14
3V3 on Mid-Layer 1 (solid, remove dead copper): 3681,3240.63 3681,3140.63 3658.5,3118.13 3293.5,3118.13 3254.5,3157.13 3254.5,3222.13 3342.5,3310.13 3611.5,3310.13

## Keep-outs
Mid-Layer 1:
  region: 4396.5,3556.13 4396.5,3509.26 4495.71,3410.05 5039.97,3410.05 5104.06,3474.13 5104.06,3522.57 5027.5,3599.13 4728.47,3599.13 4711.71,3582.37 4422.74,3582.37
Bottom Layer:
  region: 3100.5,3788.57 3246.5,3788.57 3246.5,3949.17 3100.5,3949.17
  region: 4400.5,3642.13 4438.5,3642.13 4448.5,3632.13 4448.5,3618.13 4551.5,3515.13 4551.5,3352.81 4483.69,3288.04 4407.77,3288.7 4321.4,3202.33 4321.4,3157.23 4351.5,3127.13 4513.5,3127.13 4664.5,3278.13 4664.5,3579.13 4519.5,3724.13 4413.5,3724.13 4392.5,3703.13 4392.5,3650.13

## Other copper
Top Layer:
  drawing of 418 lines, arcs and shapes, not listed
  text "Lizard" at 3142.82,3649.59 h38.94 r270
Mid-Layer 1:
  region net VBUS: 3904.47,3979.57 3871,3992.36 3858.27,3979.63 3871.06,3946.16
  region net PH0: 5015.6,3192.23 4976.56,3210.31 4970.66,3207.73 4972.99,3173.62
  region net VBUS: 3742.76,3519.71 3738.5,3531.91 3728.5,3531.23 3724.8,3518.49
  region net $1N18373: 3615.23,3406.23 3607.38,3411.61 3600.31,3404.54 3605.69,3396.69
  region net 3V3: 3667.25,3699.09 3665.5,3705.13 3655.5,3705.13 3653.75,3699.09
  region net 3V3: 3590.48,3691.57 3595.85,3699.42 3588.78,3706.49 3580.94,3701.12
  region net USB_D+: 3351.55,3573.88 3342.2,3569.63 3342.2,3564.63 3351.55,3560.38
  region net USB_D-: 3351.55,3547.88 3342.2,3543.63 3342.2,3538.63 3351.55,3534.38
  region net VBUS: 3873.06,3723.12 3865.22,3728.49 3858.15,3721.42 3863.52,3713.57
  region net UART0_RX: 3909.48,3716.57 3913.09,3726.18 3909.55,3729.72 3899.94,3726.12
  region net UART0_TX: 3941.83,3747.44 3953.35,3749.63 3955.84,3754.63 3947.83,3759.53
  region net UART0_RX: 3985.45,3480.38 3994.8,3484.63 3994.8,3489.63 3985.45,3493.88
  region net UART0_TX: 4003.48,3465.57 4004.27,3472.37 4000.73,3475.9 3993.94,3475.12
  region net LPCLK: 4363.06,3466.12 4353.45,3469.72 4349.91,3466.18 4353.52,3456.57
  region net USB_D-: 4456.55,3609.88 4447.2,3605.63 4447.2,3600.63 4456.55,3596.38
  region net USB_D+: 4456.55,3584.88 4447.2,3580.63 4447.2,3575.63 4456.55,3571.38
  region net LINEOUTP: 4158.94,3385.15 4167.84,3380.84 4172.79,3385.79 4168.48,3394.7
  region net CSI_CKP: 4487.44,3553.13 4500.42,3553.63 4504.9,3558.63 4496.44,3563.2
  region net CSI_CKN: 4496.44,3538.07 4504.9,3542.63 4500.42,3547.63 4487.44,3548.13
  region net CSI_CKP: 4960.8,3588.44 4952.77,3583.63 4956.11,3578.63 4968.3,3577.21
  region net CSI_CKN: 4969.56,3573.13 4956.58,3572.63 4952.1,3567.63 4960.56,3563.07
  region net CSI_CKN: 4969.56,3573.13 4956.58,3572.63 4952.1,3567.63 4960.56,3563.07
  region net CSI_D1N: 4404.94,3527.15 4413.73,3524.37 4417.27,3527.9 4414.48,3536.7
  region net CSI_D1P: 4414.44,3509.07 4422.9,3513.63 4418.42,3518.63 4405.44,3519.13
  region net CSI_D1N: 5058.48,3449.57 5058.27,3455.37 5054.73,3458.9 5048.94,3459.12
  region net CSI_D1P: 5049.44,3465.13 5062.42,3465.63 5066.9,3470.63 5058.44,3475.2
  region net CSI_D0P: 4490.58,3483.93 4492,3471.74 4497,3468.4 4501.81,3476.43
  region net CSI_D0N: 4474.64,3476.13 4481.73,3475.37 4485.27,3478.9 4483.41,3486.4
  region net CSI_D0P: 4925.44,3489.2 4930,3480.74 4935,3485.21 4935.5,3498.2
  region net CSI_D0N: 4943.52,3497.7 4941.73,3489.9 4945.27,3486.37 4953.06,3488.15
  region net CSI_MCLK: 5047.52,3341.7 5043.91,3332.08 5047.45,3328.55 5057.06,3332.15
  region net CSI_SDA: 5086.52,3417.7 5082.91,3408.08 5086.45,3404.55 5096.06,3408.15
  region net CSI_SCK: 5118.06,3435.12 5108.45,3438.72 5104.91,3435.18 5108.52,3425.57
  region net CSI_SDA: 4474.94,3405.15 4483.73,3402.37 4487.27,3405.9 4484.48,3414.7
  region net CSI_SCK: 4499.94,3417.15 4509.55,3413.55 4513.09,3417.08 4509.48,3426.7
  region net CSI_MCLK: 4403.94,3327.15 4413.55,3323.55 4417.09,3327.08 4413.48,3336.7
  region net CSI_RSTN: 4447.83,3365.44 4459.35,3367.63 4461.84,3372.63 4453.83,3377.53
  region net CSI_RSTN: 5128.5,3400.99 5125.28,3391.45 5129.09,3388.19 5138.77,3392.22
  region net VBUS: 4407.86,3298.78 4417.9,3299.13 4421.44,3309.13 4412.36,3311.51
  region net VBUS: 4842.06,3284.12 4834.22,3289.49 4827.15,3282.42 4832.52,3274.57
  region net LPCLK: 4219.45,3466.38 4228.8,3470.63 4228.8,3475.63 4219.45,3479.88
  region net SPI0_MOSI: 4204.55,3138.88 4195.2,3135.13 4195.2,3129.13 4204.55,3125.38
  region net SPI0_MOSI: 3375.48,3267.57 3379.44,3276.83 3375.2,3281.07 3365.94,3277.12
  region net LINEOUTP: 4809.06,3283.12 4800.16,3287.43 4795.21,3282.48 4799.52,3273.57
  region net 3V3: 3667.25,3699.09 3665.5,3705.13 3655.5,3705.13 3653.75,3699.09
  region net PH0: 4141.52,3464.7 4137.56,3455.44 4141.8,3451.19 4151.06,3455.15
  region net $1N18373: 3577.75,3472.18 3579.5,3462.83 3589.5,3462.83 3591.25,3472.18
Mid-Layer 2:
  region net UART0_TX: 4971.06,3950.11 4963.22,3911.68 4966.05,3908.85 5004.47,3916.69
  region net UART0_RX: 4871.06,3950.11 4863.22,3911.68 4866.05,3908.85 4904.47,3916.69
  region net CTP_SCL: 4771.06,3950.11 4763.22,3911.68 4766.05,3908.85 4804.47,3916.69
  region net CTP_SDA: 4671.06,3950.11 4663.22,3911.68 4666.05,3908.85 4704.47,3916.69
  region net CTP_EINT: 4571.06,3950.11 4563.22,3911.68 4566.05,3908.85 4604.47,3916.69
  region net CTP_RST: 4471.06,3950.11 4463.22,3911.68 4466.05,3908.85 4504.47,3916.69
  region net PE10: 4371.06,3950.11 4363.22,3911.68 4366.05,3908.85 4404.47,3916.69
  region net $3N3727: 3621.5,3692.28 3625.86,3700.84 3619.76,3706.05 3611.23,3701.04
  region net $3N3727: 3708.18,3701.24 3699.63,3705.9 3693.97,3700.24 3698.64,3691.69
  region net DU0+: 3459.88,3508.17 3463.13,3518.14 3460.3,3520.97 3450.33,3517.72
  region net DU0-: 3464.31,3592.64 3463.5,3606.27 3459.5,3610.05 3454.5,3601.91
  region net DU0-: 3464.31,3592.64 3463.5,3606.27 3459.5,3610.05 3454.5,3601.91
  region net WL_WAKE_AP: 3925.52,3723.7 3922.27,3713.73 3925.1,3710.9 3935.06,3714.15
  region net WL_WAKE_AP: 3648.94,3663.15 3658.9,3659.9 3661.73,3662.73 3658.48,3672.7
  region net DU0-: 3973.65,3819.09 3963.89,3821.57 3961.52,3818.29 3965.72,3808.16
  region net DU0+: 3946.55,3812.88 3937.2,3808.13 3937.2,3804.13 3946.55,3799.38
  region net UART0_RX: 3988.48,3486.57 3988.91,3493.72 3986.09,3496.55 3978.94,3496.12
  region net UART0_TX: 4003.48,3465.57 4006.73,3475.54 4003.9,3478.37 3993.94,3475.12
  region net GND: 4013.25,3774.09 4011.5,3783.43 4001.5,3783.43 3999.75,3774.09
  region net PE10: 4057.48,3624.57 4060.73,3634.54 4057.9,3637.37 4047.94,3634.12
  region net GND: 3885.45,3804.38 3894.8,3806.13 3894.8,3816.13 3885.45,3817.88
  region net VBUS: 4848.25,3281.09 4846.5,3290.43 4836.5,3290.43 4834.75,3281.09
  region net VBUS: 4826.94,3468.15 4834.78,3462.78 4841.85,3469.85 4836.48,3477.7
  region net LINEOUTP: 4800.19,3544.43 4804,3535.73 4811,3540.41 4811.42,3551.93
  region net CTP_SCL: 3945.75,3484.18 3950.5,3474.83 3954.5,3474.83 3959.25,3484.18
  region net CTP_SCL: 3961.48,3489.57 3964.73,3499.54 3961.9,3502.37 3951.94,3499.12
  region net CTP_SDA: 3942.52,3520.7 3939.27,3510.73 3942.1,3507.9 3952.06,3511.15
  region net CTP_SDA: 3958.8,3514.87 3967.19,3520.13 3966.28,3524.13 3955.8,3528.04
  region net CTP_EINT: 3975.45,3533.38 3984.8,3538.13 3984.8,3542.13 3975.45,3546.88
  region net CTP_EINT: 3963.55,3546.88 3954.2,3542.13 3954.2,3538.13 3963.55,3533.38
  region net CTP_RST: 3980.55,3565.88 3971.2,3561.13 3971.2,3557.13 3980.55,3552.38
  region net CTP_RST: 3992.45,3552.38 4001.8,3557.13 4001.8,3561.13 3992.45,3565.88
  region net LINEOUTP: 4817.48,3273.57 4821.79,3282.48 4816.84,3287.43 4807.94,3283.12
  region net CTP_RST: 3371.94,3223.15 3381.9,3219.9 3384.73,3222.73 3381.48,3232.7
  region net CTP_SDA: 3381.98,3184.14 3379.91,3189.72 3377.09,3192.55 3369.45,3189.17
  region net CTP_SCL: 3453.25,3173.09 3448.5,3182.43 3444.5,3182.43 3439.75,3173.09
  region net CTP_EINT: 3513.56,3151.2 3505.55,3146.13 3509.13,3142.13 3522.56,3141.13
  region net CTP_EINT: 3513.56,3151.2 3505.55,3146.13 3509.13,3142.13 3522.56,3141.13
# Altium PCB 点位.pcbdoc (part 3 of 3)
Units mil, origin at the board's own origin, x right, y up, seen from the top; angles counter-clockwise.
Board outline 2817.44 x 1578.14 mil, 2 copper layers (Top Layer, Bottom Layer); 132 components, 113 nets, 538 pads, 285 vias.

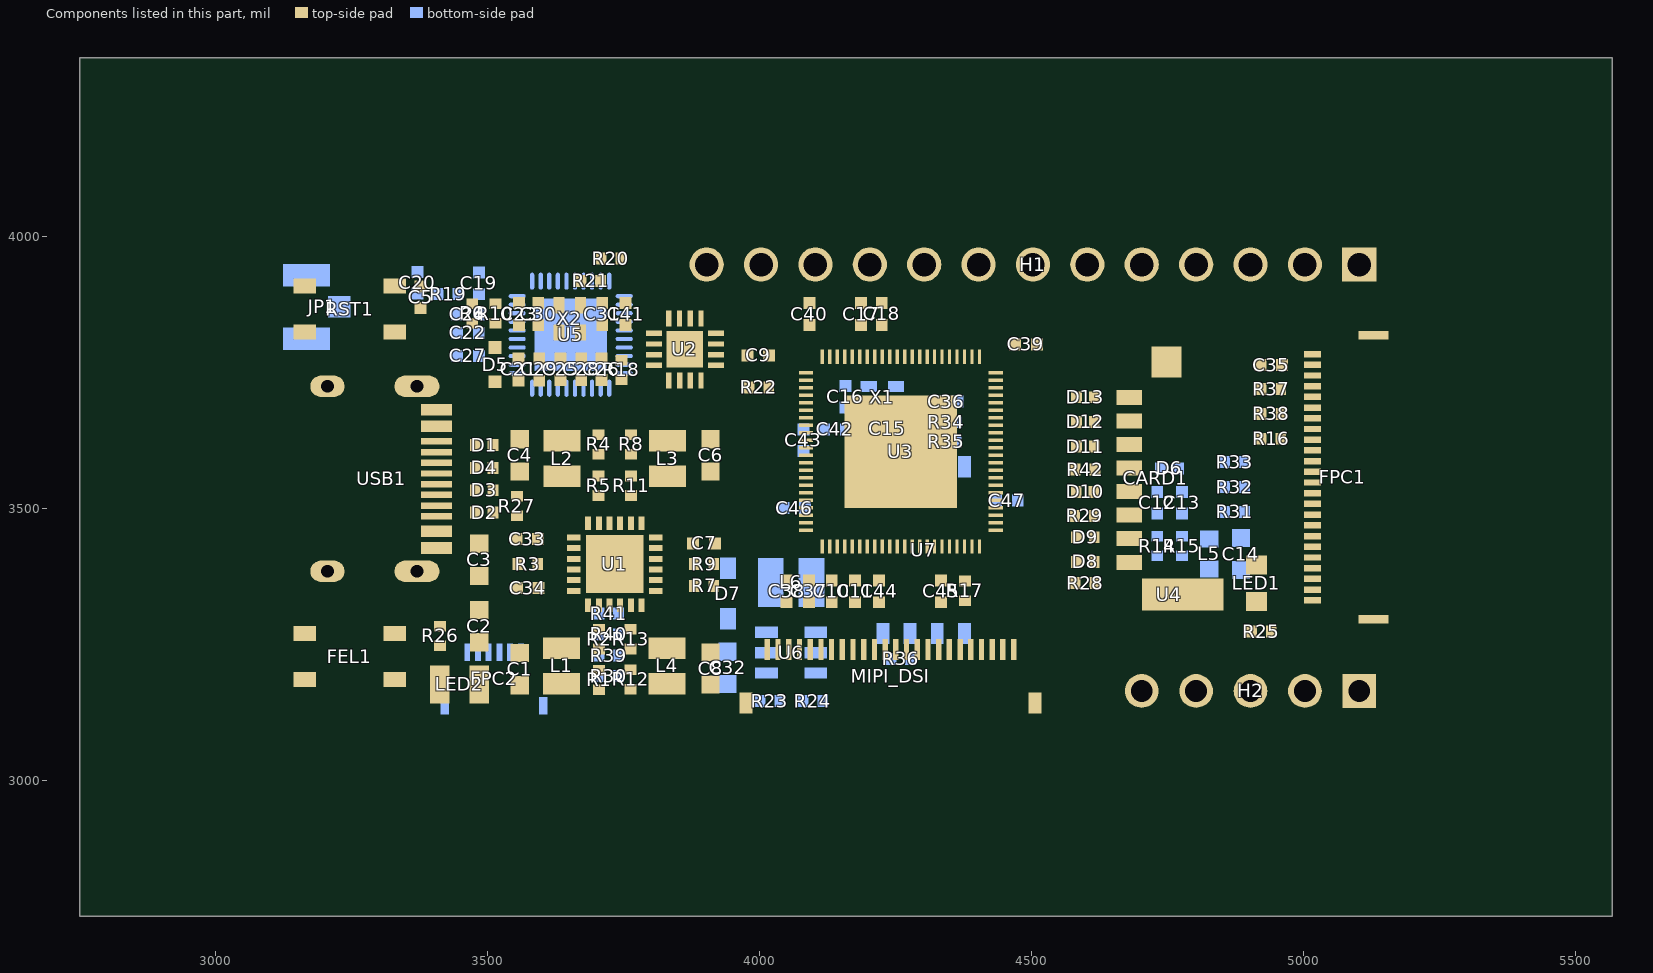
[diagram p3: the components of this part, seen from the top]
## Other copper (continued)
Bottom Layer:
  region net $3N3729: 3276.19,3873.95 3276.28,3894.45 3247.18,3889.82 3247.18,3850.45
  region net $3N3729: 3370.64,3884.48 3399.4,3882.8 3399.4,3904.8 3370.64,3904.48
  region net $3N3728: 3483.33,3903.8 3455.09,3904.8 3455.09,3882.8 3483.33,3883.8
  region net $3N3728: 3445.25,3903.8 3445.25,3883.8 3472.64,3882.48 3472.64,3904.48
  region net $3N3728: 3523.84,3882.15 3524.61,3902.15 3494.64,3904.48 3494.64,3882.48
  region net $3N3729: 3329.7,3882.52 3359.64,3883.48 3359.64,3905.48 3329.7,3902.61
  region net $3N3729: 3408.56,3884.48 3408.56,3904.48 3381.64,3905.48 3381.64,3883.48
  region net 3V3: 4718.5,3576.13 4718.5,3570.13 4727.16,3562.63 4727.16,3583.63
  region net $2N11171: 4735.92,3363.59 4735.85,3367.84 4729.85,3367.84 4729.78,3363.59
  region net $2N10833: 4776.94,3360.62 4778.48,3362.26 4774.24,3366.5 4772.6,3364.96
  region net $2N10833: 4779.36,3393.62 4786.86,3402.62 4765.86,3402.62 4773.36,3393.62
  region net $2N10977: 4779.36,3467.31 4773.36,3467.31 4765.86,3458.31 4786.86,3458.31
  region net $2N10977: 4779.36,3470.3 4786.86,3479.3 4765.86,3479.3 4773.36,3470.3
  region net $2N11171: 4735.85,3393.62 4742.04,3402.62 4722.35,3402.62 4729.85,3393.62
  region net $2N11292: 4728.04,3467.31 4720.54,3458.31 4741.54,3458.31 4734.04,3467.31
  region net LINEOUTP: 4745.58,3551.91 4720.05,3541.3 4742.05,3519.3 4752.65,3544.84
  region net $2N11292: 4728.04,3470.3 4734.04,3470.3 4741.54,3479.3 4720.54,3479.3
  region net $2N11927: 4823.5,3362.13 4831.5,3362.13 4841.5,3372.57 4813.5,3372.57
  region net $2N11927: 4852.86,3391.32 4843.86,3398.82 4843.86,3377.82 4852.86,3385.32
  region net VBUS: 4831.85,3474.18 4821.85,3474.18 4809.84,3459.18 4843.86,3459.18
  region net $2N11927: 4859.12,3391.32 4859.12,3385.32 4868.12,3377.82 4868.12,3398.82
  region net HXIN: 4174.5,3723.05 4174.5,3727.05 4168.5,3732.05 4168.5,3718.05
  region net HXOUT: 4252.49,3663.05 4247.49,3657.05 4261.49,3657.05 4256.49,3663.05
  region net HXIN: 4179.5,3723.05 4185.5,3718.05 4185.5,3732.05 4179.5,3727.05
  region net HXIN: 4202.5,3740.05 4198.5,3740.05 4193.5,3734.05 4207.5,3734.05
  region net HXOUT: 4233.43,3698.3 4235.5,3689.15 4250.4,3694.05 4239.08,3698.3
  region net HXOUT: 4252.49,3668.05 4256.49,3668.05 4261.49,3674.05 4247.49,3674.05
  region net $3N3727: 3565.69,3913.53 3578.36,3903.53 3578.36,3931.53 3565.69,3921.53
  region net HX1: 3615.13,3938.74 3611.13,3938.74 3609.19,3929.34 3617.07,3929.34
  region net HX2: 3630.88,3938.74 3626.88,3938.74 3624.94,3929.34 3632.82,3929.34
  region net AP_WAKE_BT: 3642.63,3938.26 3640.69,3929.34 3648.57,3929.34 3646.63,3938.26
  region net BT_WAKE_AP: 3658.37,3937 3656.43,3929.34 3664.31,3929.34 3662.37,3937
  region net UART2_CTS: 3674.12,3933.75 3672.18,3929.34 3680.06,3929.34 3678.12,3933.75
  region net UART2_RTS: 3689.87,3933.5 3687.93,3929.34 3695.81,3929.34 3693.87,3933.5
  region net UART2_TX: 3705.62,3934.25 3703.68,3929.34 3711.56,3929.34 3709.62,3934.25
  region net $3N3721: 3731.55,3707.91 3727.31,3732.54 3720.75,3705.98 3731.05,3702.76
  region net BT_RSTN: 3689.87,3699.53 3693.87,3699.53 3695.81,3708.92 3687.93,3708.92
  region net WL_REG_ON: 3674.12,3699.53 3678.12,3699.53 3680.06,3708.92 3672.18,3708.92
  region net LPCLK: 3748.9,3738.33 3752.9,3738.33 3757.9,3744.33 3743.9,3744.33
  region net SDC1_D2: 3769.12,3797.51 3762.71,3799.45 3762.71,3791.58 3769.12,3793.51
  region net SDC1_CLK: 3770.37,3813.26 3762.71,3815.2 3762.71,3807.33 3770.37,3809.26
  region net SDC1_D3: 3772.1,3829 3762.71,3830.94 3762.71,3823.07 3772.1,3825
  region net SDC1_D1: 3772.1,3840.75 3772.1,3844.75 3762.71,3846.69 3762.71,3838.82
  region net SDC1_D0: 3772.1,3860.5 3762.71,3862.44 3762.71,3854.57 3772.1,3856.5
  region net SDC1_CMD: 3772.1,3876.25 3762.71,3878.19 3762.71,3870.32 3772.1,3872.25
  region net $3N3723: 3506.46,3854.5 3506.46,3862.5 3494.46,3867.36 3494.46,3845.36
  region net 3V3: 3503.5,3817.13 3503.5,3825.13 3494.46,3833.36 3494.46,3811.36
  region net $3N3727: 3500.32,3791.3 3494.67,3796.96 3474.7,3791.13 3494.49,3771.33
  region net $3N3727: 3487.49,3760.13 3494.49,3769.13 3472.49,3769.13 3479.49,3760.13
  region net DSI_PWM: 4049.34,3130.29 4051.01,3134.28 4046.77,3145.59 4038.02,3134.53
  region net DSI_PWM: 4034.92,3162.53 4029.92,3156.53 4043.92,3156.53 4038.92,3162.53
  region net LEDK: 4077.92,3162.54 4072.92,3156.54 4086.92,3156.54 4081.92,3162.54
  region net LEDA: 3950.5,3279.8 3932.5,3279.8 3924.19,3252.8 3957.65,3252.8
  region net LEDA: 3969.65,3240.06 3957.65,3250.06 3957.65,3222.06 3969.65,3232.06
  region net VBUS: 4021.72,3300.2 4044.12,3318.24 3996.92,3318.24 4003.72,3300.2
  region net $1N26471: 4104.32,3291.24 4118.92,3318.24 4071.72,3318.24 4086.32,3291.24
  region net 3V3: 4364.5,3638.13 4371.35,3647.13 4351.66,3647.13 4358.5,3638.13
  region net 3V3: 4366.51,3678.13 4360.51,3678.13 4353.01,3669.13 4371.35,3669.13
  region net SPI0_CS: 4312.74,3641.82 4326.88,3647.13 4315.66,3660.66 4310.36,3646.52
  region net 3V3: 4380.34,3625.13 4371.34,3632.63 4371.34,3611.63 4380.34,3619.13
  region net 3V3: 4364.5,3642.13 4358.5,3642.13 4351.66,3633.13 4371.34,3633.13
  region net SPI0_WP: 4327.5,3605.13 4332.5,3611.13 4318.5,3611.13 4323.5,3605.13
  region net 3V3: 4239.5,3206.14 4243.5,3206.14 4248.5,3212.14 4234.5,3212.14
  region net 3V3: 4227.41,3234.39 4231.66,3223.08 4240.4,3234.14 4229.08,3238.38
  region net SPI0_HOLD: 4275.5,3240.14 4270.5,3234.14 4284.5,3234.14 4279.5,3240.14
  region net SPI0_WP: 4310.46,3564.92 4310.46,3559.26 4315.2,3556.93 4314.7,3576.23
  region net SPI0_WP: 4327.5,3602.33 4323.5,3602.33 4318.5,3596.33 4332.5,3596.33
  region net SPI0_MISO: 4274.5,3550.93 4278.5,3550.93 4283.5,3556.93 4269.5,3556.93
  region net SPI0_CS: 4235.47,3601.64 4221.33,3596.33 4238.3,3588.56 4242.54,3601.64
  region net SPI0_CS: 4224.5,3556.13 4228.5,3556.13 4233.5,3556.93 4219.5,3556.93
  region net 3V3: 4224.5,3243.93 4228.5,3243.93 4233.5,3249.93 4219.5,3249.93
  region net SPI0_MOSI: 4359.4,3256.07 4359.4,3248.99 4369.17,3249.93 4364.7,3270.21
  region net SPI0_MOSI: 4378.5,3295.33 4374.5,3295.33 4369.5,3289.33 4383.5,3289.33
  region net SPI0_CLK: 4327.5,3295.13 4323.5,3295.13 4318.5,3289.33 4332.5,3289.33
  region net SPI0_HOLD: 4271.5,3295.33 4266.5,3289.33 4280.5,3289.33 4275.5,3295.33
  region net SPI0_HOLD: 4275.5,3243.93 4279.5,3243.93 4284.5,3249.93 4270.5,3249.93
  region net LEDA: 3950.5,3250.23 3956.25,3277.23 3926.75,3277.23 3932.5,3250.23
  region net $1N26471: 4104.32,3309.39 4086.32,3309.39 4082.02,3282.39 4124.22,3282.39
  region net LEDK: 4085.6,3182.44 4091.26,3182.44 4102.57,3186.69 4082.77,3186.69
  region net LEDK: 4064.5,3203.14 4064.5,3191.14 4082.02,3186.69 4082.02,3207.59
  region net DSI_PWM: 4024.58,3182.44 4030.24,3182.44 4033.07,3186.69 4013.27,3186.69
  region net LEDA: 3979.62,3242.13 3979.62,3234.13 3991.62,3224.13 3991.62,3244.99
  region net VBUS: 4021.72,3300.2 4003.72,3300.2 3991.62,3282.39 4033.82,3282.39
  region net SPK-: 4733.44,3162.19 4736.39,3190.95 4729.32,3198.02 4700.56,3195.07
  region net SPK+: 4804.44,3195.07 4776.39,3197.32 4769.32,3190.24 4771.56,3162.19
  region net 3V3: 4366.51,3676.13 4374.01,3685.13 4353.01,3685.13 4360.51,3676.13
  region net 0V9: 4120.5,3625.13 4128,3634.13 4107.49,3634.13 4114.5,3625.13
  region net 0V9: 4100.5,3608.13 4091.5,3615.63 4091.5,3594.63 4100.5,3602.13
  region net 3V3: 4888.34,3513.31 4881.5,3504.31 4901.18,3504.31 4894.34,3513.31
  region net SDC0_CMD: 4842.22,3510.67 4839.13,3505.27 4845.5,3488.3 4859.19,3504.31
  region net 3V3: 4888.34,3518.99 4894.34,3518.99 4901.18,3527.99 4881.5,3527.99
  region net 3V3: 4888.34,3558.99 4881.5,3549.99 4901.18,3549.99 4894.34,3558.99
  region net SDC0_D3: 4842.22,3556.36 4839.13,3550.96 4845.5,3533.99 4859.19,3549.99
  region net 3V3: 4888.34,3564.68 4894.34,3564.68 4901.18,3573.68 4881.5,3573.68
  region net 3V3: 4888.34,3602.29 4881.5,3595.68 4901.18,3595.68 4894.34,3602.29
  region net SDC0_D2: 4841.35,3602.04 4845.5,3587.29 4865.18,3595.68 4849.83,3602.04
  region net CTP_EINT: 3537,3207.58 3545,3207.58 3546.5,3219.58 3535.5,3219.58
  region net CTP_SCL: 3525.4,3207.58 3526.9,3219.58 3515.9,3219.58 3517.4,3207.58
  region net CTP_SDA: 3505.7,3207.58 3507.2,3219.58 3496.2,3219.58 3497.7,3207.58
  region net CTP_SDA: 3497.7,3259.33 3496.2,3251.08 3507.2,3251.08 3505.7,3259.33
  region net CTP_RST: 3478,3213.63 3486,3213.63 3487.5,3219.58 3476.5,3219.58
  region net CTP_RST: 3478,3263.08 3476.5,3251.08 3487.5,3251.08 3486,3263.08
  region net CTP_EINT: 3682.66,3186.13 3694.66,3180.14 3694.66,3202.14 3682.66,3194.13
  region net 3V3: 3725.35,3179.53 3727.73,3174.83 3741.87,3180.14 3730.66,3193.67
  region net 3V3: 3743,3209.64 3738,3209.64 3731.75,3202.14 3749.25,3202.14
  region net CTP_SCL: 3682.66,3233.14 3682.66,3225.14 3694.66,3218.14 3694.66,3240.14
  region net 3V3: 3743,3210.64 3749.25,3218.14 3731.75,3218.14 3738,3210.64
  region net 3V3: 3743,3247.64 3738,3247.64 3731.75,3240.14 3749.25,3240.14
  region net CTP_SDA: 3688.5,3264.14 3694.66,3257.14 3694.66,3279.14 3688.5,3272.14
  region net 3V3: 3743,3249.64 3749.25,3257.14 3731.75,3257.14 3738,3249.64
  region net 3V3: 3743,3286.64 3738,3286.64 3731.75,3279.14 3749.25,3279.14
  region net CTP_RST: 3686.17,3299.46 3686.17,3288.15 3707.3,3295.14 3694.66,3317.14
  region net 3V3: 3743,3287.64 3749.25,3295.14 3731.75,3295.14 3738,3287.64
  region net $1N18373: 3840.72,3414.01 3831.37,3412.26 3831.37,3402.26 3840.72,3400.51
  region net $1N18373: 3620.62,3390.5 3629.97,3392.25 3629.97,3402.25 3620.62,3404
  region net $3N3727: 3567.99,3911 3577.53,3913.53 3578.06,3921.53 3568.89,3924.47
  region net HX2: 3625.51,3950.7 3626.88,3937.64 3630.88,3934.44 3636.05,3942.27
  region net HX1: 3605.78,3943.47 3611.13,3935.33 3615.13,3936.55 3618.69,3947.41
  region net $3N3727: 3619.65,3697.6 3617.13,3707.15 3609.13,3707.71 3606.18,3698.54
  region net 3V3: 3667.25,3699.09 3664.5,3708.43 3656.5,3708.43 3653.75,3699.09
  region net $3N3727: 3714.37,3698.21 3711.62,3707.55 3703.62,3707.55 3700.87,3698.21
  region net $3N3721: 3738.06,3708.12 3728.1,3711.37 3725.27,3708.54 3728.52,3698.57
  region net 3V3: 3588.34,3697.99 3585.63,3707.37 3577.63,3707.49 3574.84,3698.18
  region net $1N22582: 3839.25,3714.09 3836.5,3723.43 3828.5,3723.43 3825.75,3714.09
  region net $1N22582: 3940.55,3788.88 3936.5,3786.13 3936.5,3778.13 3940.55,3775.38
  region net SDC1_CLK: 3956.1,3713.8 3961.5,3706.05 3965.5,3708.03 3968.19,3719.8
  region net SDC1_D3: 3937.75,3692.18 3942.5,3682.83 3946.5,3682.83 3951.25,3692.18
  region net SDC1_D1: 3853.55,3688.88 3844.2,3684.13 3844.2,3680.13 3853.55,3675.38
  region net SDC1_CMD: 4074.06,3775.12 4064.1,3778.37 4061.27,3775.54 4064.52,3765.57
  region net USB_ID: 4116.25,3686.09 4112,3695.43 4107,3695.43 4102.75,3686.09
  region net SDC1_D0: 4053.16,3767.73 4042.99,3772.47 4039.47,3770.33 4041.64,3760.7
  region net WL_REG_ON: 3682.99,3678.37 3678.12,3687.51 3674.12,3687.35 3669.5,3677.8
  region net BT_RSTN: 3718.17,3680.53 3710.41,3675.13 3712.4,3671.13 3724.17,3668.44
  region net SDC1_D2: 4113.52,3741.7 4110.27,3731.73 4113.1,3728.9 4123.06,3732.15
  region net $3N3722: 3580.94,3940.15 3589.49,3935.49 3595.15,3941.14 3590.48,3949.7
  region net WL_WAKE_AP: 3643.55,3678.88 3634.2,3674.13 3634.2,3670.13 3643.55,3665.38
  region net $3N3727: 3487.42,3756.34 3487.49,3767.52 3479.49,3772.86 3476.19,3763.83
  region net AP_WAKE_BT: 3648.75,3958.18 3653.5,3949.13 3657.5,3949.13 3662.25,3958.18
  region net BT_WAKE_AP: 3673.31,3960.4 3671.67,3951.13 3676.01,3949.81 3686.23,3956.48
  region net LPCLK: 3758.06,3726.12 3752.31,3725.15 3749.49,3722.32 3748.52,3716.57
  region net LPCLK: 3750.75,3711.18 3755,3701.83 3760,3701.83 3764.25,3711.18
  region net HXOUT: 4215.75,3746.18 4220.5,3741.13 4224.5,3741.13 4229.25,3746.18
  region net HXIN: 4193.45,3743.47 4198.5,3734.63 4202.5,3735.07 4206.87,3744.96
  region net 0V9: 4117.58,3609.13 4099.97,3608.13 4094.61,3602.13 4105.58,3595.71
  region net 0V9: 4126.5,3605.07 4120.5,3617.53 4114.5,3617.53 4108.5,3605.07
  region net UART2_CTS: 4363.06,3816.12 4353.1,3819.37 4350.27,3816.54 4353.52,3806.57
  region net UART2_RTS: 4379.09,3810.34 4373.89,3800.14 4375.84,3796.43 4385.37,3798.39
  region net UART2_TX: 4407.52,3807.7 4404.27,3797.73 4407.1,3794.9 4417.06,3798.15
  region net UART2_RX: 4396.58,3758.76 4386.38,3767.08 4381.27,3766.54 4383.16,3757.34
  region net USB_ID: 3548.48,3933.57 3552.09,3943.18 3548.55,3946.72 3538.94,3943.12
  region net 3V3: 3665.44,3148.13 3677.9,3154.63 3677.9,3159.63 3665.44,3166.13
  region net SPI0_CLK: 4273.42,3375.5 4283.62,3367.18 4286.91,3369.55 4286.84,3376.93
  region net SPI0_HOLD: 4317.33,3406.5 4307.44,3402.13 4306.99,3398.13 4315.83,3393.09
  region net SPI0_MOSI: 4297.75,3376.18 4301.03,3366.83 4303.09,3374.55 4311.25,3376.18
  region net SPI0_MOSI: 4297.75,3376.18 4297.09,3368.55 4301.03,3366.83 4311.25,3376.18
  region net SPI0_MOSI: 4297.75,3376.18 4302.5,3373.13 4306.5,3373.13 4311.25,3376.18
  region net SPI0_MISO: 4301.25,3463.09 4296.5,3472.43 4292.5,3472.43 4287.75,3463.09
  region net SPI0_CS: 4275.37,3455.46 4278.62,3465.43 4275.79,3468.26 4265.83,3465.01
  region net SPI0_WP: 4323.06,3466.12 4313.1,3469.37 4310.27,3466.54 4313.52,3456.57
  region net 3V3: 4406.06,3619.12 4396.8,3623.07 4392.56,3618.83 4396.52,3609.57
  region net LEDK: 4070.46,3190.39 4079.8,3191.14 4079.8,3203.14 4070.45,3203.89
  region net LEDA: 3983.45,3231.38 3992.8,3234.13 3992.8,3242.13 3983.45,3244.88
  region net LEDA: 3970.15,3243.33 3961.32,3240.06 3963.21,3232.06 3973.26,3230.2
  region net DSI_PWM: 4036.01,3183.39 4026.04,3186.64 4023.22,3183.81 4026.47,3173.84
  region net DSI_PWM: 4029.76,3167.43 4034.92,3158.81 4038.92,3159.48 4043.08,3169.64
  region net DSI_CKP: 4467.17,3706.44 4482.1,3705.13 4489.64,3710.13 4478.42,3713.9
  region net DSI_CKN: 4478.48,3688.57 4478.27,3694.37 4474.73,3697.9 4468.94,3698.12
  region net DSI_CKP: 4389.94,3151.15 4399.55,3147.55 4403.09,3151.08 4399.48,3160.7
  region net DSI_CKN: 4417.28,3153.31 4429.13,3155.13 4432.01,3160.13 4424.03,3165
  region net DSI_D1P: 4411.45,3681.38 4420.8,3685.63 4420.8,3690.63 4411.45,3694.88
  region net DSI_D1N: 4411.45,3653.38 4420.8,3657.63 4420.8,3662.63 4411.45,3666.88
  region net DSI_D0P: 4483.09,3625.94 4492.72,3618.38 4498.58,3619.59 4496.31,3628.66
  region net DSI_D0N: 4463.94,3623.15 4473.55,3619.55 4477.09,3623.08 4473.48,3632.7
  region net DSI_D1N: 4335.94,3185.46 4347.48,3187.63 4349.98,3192.63 4341.98,3197.53
  region net DSI_D1P: 4342.48,3167.57 4345.79,3176.89 4342.25,3180.42 4332.94,3177.12
  region net DSI_D0P: 4427.94,3268.15 4436.73,3265.37 4440.27,3268.9 4437.48,3277.7
  region net DSI_D0N: 4445.75,3270.18 4450,3260.83 4455,3260.83 4459.25,3270.18
  region net 1V8: 4355.25,3409.09 4352.5,3415.15 4344.5,3415.15 4341.75,3409.09
  region net 3V3: 4250.96,3204.22 4242.91,3205.55 4240.08,3202.72 4241.42,3194.67
  region net DSI_PWM: 4419.48,3720.57 4419.91,3727.72 4417.09,3730.55 4409.94,3730.12
  region net DSI_RST: 4345.77,3128.14 4355.27,3125.72 4358.09,3128.55 4354.39,3138.53
  region net DSI_RST: 4501.83,3721.73 4509.59,3727.13 4507.6,3731.13 4495.83,3733.83
  region net 3V3: 4724.45,3566.38 4733.8,3570.13 4733.8,3576.13 4724.45,3579.88
  region net 3V3: 3768.52,3903.7 3763.85,3895.14 3769.51,3889.49 3778.06,3894.15
  region net $1N18373: 3421.8,3316.23 3431.82,3318.13 3433.65,3326.13 3424.8,3329.39
  region net USB_ID: 4054.06,3872.12 4044.45,3875.72 4040.91,3872.18 4044.52,3862.57
  region net VBUS: 4820.34,3471.68 4821.85,3462.2 4831.85,3461.48 4833.8,3470.71
  region net LINEOUTP: 4795.83,3559.18 4786.66,3557.13 4787.78,3547.13 4797.33,3545.76
  region net USB_ID: 4065.17,3793.09 4074.06,3797.63 4073.5,3802.63 4063.67,3806.5
  region net LPCLK: 4207.55,3479.88 4198.2,3475.63 4198.2,3470.63 4207.55,3466.38
  region net SPI0_MOSI: 4216.45,3125.38 4225.8,3129.63 4225.8,3134.63 4216.45,3138.88
  region net 3V3: 3667.25,3699.09 3664.5,3708.43 3656.5,3708.43 3653.75,3699.09
  region net SDC0_D2: 4715.75,3683.18 4719.5,3673.83 4725.5,3673.83 4729.25,3683.18
  region net SDC0_D3: 4722.94,3627.15 4732.2,3623.19 4736.44,3627.44 4732.48,3636.7
  region net SDC0_CMD: 4724.7,3601.21 4736.56,3602.13 4740.56,3608.13 4732.2,3612.44
  region net 3V3: 4870.94,3613.15 4880.2,3609.19 4884.44,3613.44 4880.48,3622.7
  region net CTP_RST: 3371.94,3223.15 3380.49,3218.49 3386.15,3224.14 3381.48,3232.7
  region net CTP_SDA: 3381.36,3176.75 3390.08,3180.13 3387.25,3188.13 3376.86,3189.48
  region net CTP_SCL: 3449.86,3158.78 3460.25,3160.13 3463.08,3168.13 3454.36,3171.51
  region net CTP_EINT: 3531.48,3149.57 3536.15,3158.12 3530.49,3163.78 3521.94,3159.12

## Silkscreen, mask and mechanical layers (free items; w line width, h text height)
Top Overlay:
  text "YuzukiHD x 100ASK" at 4215.15,3841.89 h51.92
  text "1" at 5011.32,3802.13 h39.22 r90
  text "RST" at 3226.18,3752.45 h38.94
  text "Lizard" at 3142.82,3649.59 h38.94 r270
  text "TF Card" at 4760.18,3445.97 h38.94 r90
  text "V851S" at 4062.18,3411.39 h38.94 r90
  text "1.1" at 3246.18,3406.45 h38.94
  text "FEL" at 3233.18,3309.45 h38.94
  text "Camera" at 4977.18,3283.68 h38.94 r90
  text "Display" at 4305.34,3272.45 h38.94
  text "-SPK+" at 4644.76,3221.45 h38.94
  text "24" at 4539.89,3188.45 h38.94
Bottom Overlay:
  text "GND" at 4047.82,3900.46 h38.94 r90
  text "PE11" at 4147.82,3899.92 h38.94 r90
  text "PE12" at 4250.8,3900.49 h38.94 r90
  text "PE10" at 4450.48,3899.92 h38.94 r90
  text "PE14" at 4551.11,3899.92 h38.94 r90
  text "PE13" at 4348.82,3899.17 h38.94 r90
  text "PH13" at 4647.82,3898.92 h38.94 r90
  text "PH12" at 4750.82,3898.07 h38.94 r90
  text "PH11" at 4849.82,3897.17 h38.94 r90
  text "TX0" at 5046.82,3897.46 h38.94 r90
  text "RX0" at 4948.82,3896.36 h38.94 r90
  text "GND" at 5146.82,3896.46 h38.94 r90
  text "5V" at 3946.82,3892.75 h38.94 r90
  text "Yuzukilizard" at 5096.19,3670.55 h71.39
  text "CERN-OHL-S" at 5100.21,3618.45 h38.94
  text "OTG" at 3273.82,3611.46 h38.94 r90
  text "UART" at 3125.18,3472.1 h38.94 r270
  text "GND" at 5145.82,3321.21 h38.94 r90
  text "PH0" at 5046.82,3319.21 h38.94 r90
  text "3V3" at 4947.82,3316.21 h38.94 r90
  text "SP+" at 4847.82,3314.21 h38.94 r90
  text "SP-" at 4747.82,3313.21 h38.94 r90
  text "1" at 3404.5,3188.31 h39.22
  text "CTP" at 3761.18,3117.45 h38.94
Mechanical 1:
  lines w10: 3102.5,3118.13 3102.5,3991.13 3122.5,4011.13 5146.5,4011.13 5166.5,3991.13 5166.5,3118.13 5146.5,3098.13 3122.5,3098.13 3102.5,3118.13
